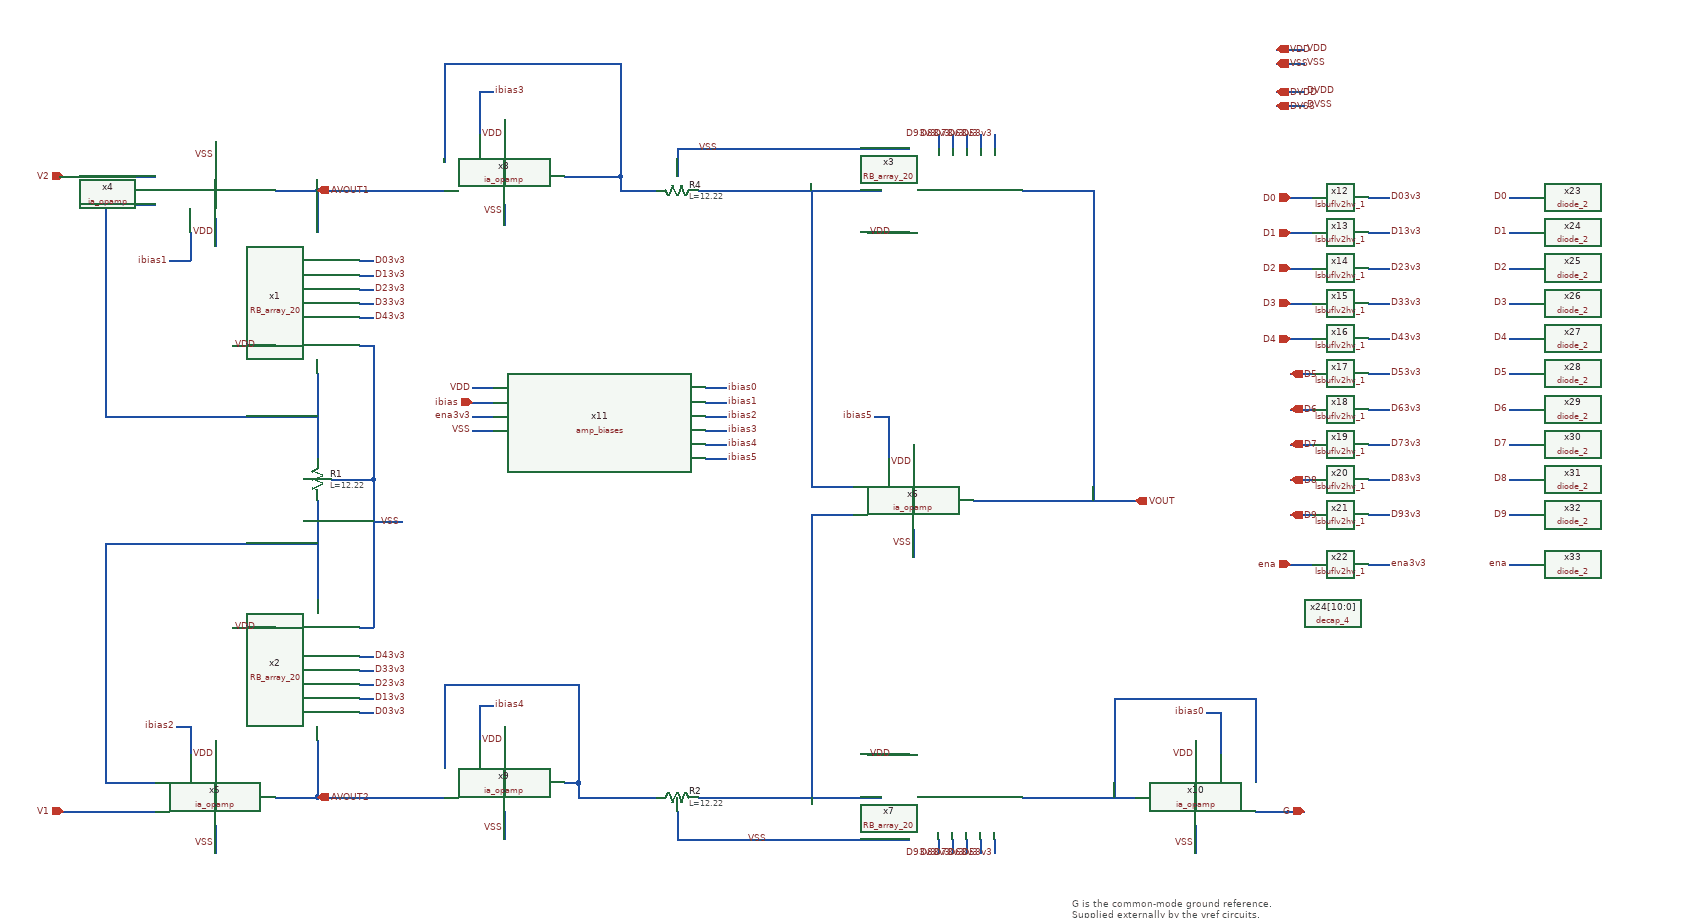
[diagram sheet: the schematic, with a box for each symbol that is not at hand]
v {xschem version=3.4.5 file_version=1.2
}
G {}
K {}
V {}
S {}
E {}
T {G is the common-mode ground reference.
Supplied externally by the vref circuits.} -70 60 0 0 0.4 0.4 {}
N -210 -500 20 -500 {
lab=VOUT}
N -580 -940 -360 -940 {
lab=#net1}
N -140 -940 -40 -940 {
lab=VOUT}
N -40 -940 -40 -500 {
lab=VOUT}
N -580 -80 -360 -80 {
lab=#net2}
N -440 -520 -380 -520 {
lab=#net1}
N -440 -940 -440 -520 {
lab=#net1}
N -440 -480 -380 -480 {
lab=#net2}
N -440 -480 -440 -80 {
lab=#net2}
N -1140 -940 -1140 -880 {
lab=AVOUT1}
N -1140 -660 -1140 -560 {
lab=#net3}
N -1140 -500 -1140 -360 {
lab=#net4}
N -1140 -140 -1140 -80 {
lab=AVOUT2}
N -1440 -920 -1370 -920 {
lab=#net3}
N -1440 -620 -1140 -620 {
lab=#net3}
N -1440 -100 -1370 -100 {
lab=#net4}
N -1440 -440 -1440 -100 {
lab=#net4}
N -1440 -440 -1140 -440 {
lab=#net4}
N -140 -80 20 -80 {
lab=G}
N -295 -580 -295 -540 {
lab=VDD}
N -295 -460 -295 -420 {
lab=VSS}
N -1505 -960 -1370 -960 {
lab=V2}
N -1500 -60 -1370 -60 {
lab=V1}
N -1285 -160 -1285 -120 {
lab=VDD}
N -1285 -40 -1285 0 {
lab=VSS}
N -1285 -900 -1285 -860 {
lab=VDD}
N -1285 -1010 -1285 -980 {
lab=VSS}
N -1060 -690 -1060 -530 {
lab=VSS}
N -1060 -530 -1060 -330 {
lab=VSS}
N -1060 -470 -1020 -470 {
lab=VSS}
N -1440 -890 -1440 -620 {
lab=#net3}
N -1440 -920 -1440 -890 {
lab=#net3}
N -1140 -160 -1140 -140 {
lab=AVOUT2}
N -1080 -320 -1060 -320 {
lab=VSS}
N -1060 -330 -1060 -320 {
lab=VSS}
N -1080 -720 -1060 -720 {
lab=VSS}
N -1060 -720 -1060 -690 {
lab=VSS}
N -1120 -530 -1060 -530 {
lab=VSS}
N -600 -940 -580 -940 {
lab=#net1}
N -630 -1000 -300 -1000 {
lab=VSS}
N -630 -1000 -630 -960 {
lab=VSS}
N -360 -940 -340 -940 {
lab=#net1}
N -360 -80 -340 -80 {
lab=#net2}
N -600 -80 -580 -80 {
lab=#net2}
N -630 -20 -300 -20 {
lab=VSS}
N -1080 -760 -1060 -760 {
lab=D43v3}
N -1080 -780 -1060 -780 {
lab=D33v3}
N -1080 -800 -1060 -800 {
lab=D23v3}
N -1080 -820 -1060 -820 {
lab=D13v3}
N -1080 -840 -1060 -840 {
lab=D03v3}
N -1080 -280 -1060 -280 {
lab=D43v3}
N -1080 -260 -1060 -260 {
lab=D33v3}
N -1080 -240 -1060 -240 {
lab=D23v3}
N -1080 -220 -1060 -220 {
lab=D13v3}
N -1080 -200 -1060 -200 {
lab=D03v3}
N -180 -20 -180 0 {
lab=D53v3}
N -200 -20 -200 0 {
lab=D63v3}
N -220 -20 -220 0 {
lab=D73v3}
N -240 -20 -240 0 {
lab=D83v3}
N -260 -20 -260 0 {
lab=D93v3}
N -180 -1020 -180 -1000 {
lab=D53v3}
N -200 -1020 -200 -1000 {
lab=D63v3}
N -220 -1020 -220 -1000 {
lab=D73v3}
N -240 -1020 -240 -1000 {
lab=D83v3}
N -260 -1020 -260 -1000 {
lab=D93v3}
N -1140 -680 -1140 -660 {
lab=#net3}
N -1260 -720 -1200 -720 {
lab=VDD}
N -1260 -320 -1200 -320 {
lab=VDD}
N -360 -880 -300 -880 {
lab=VDD}
N -360 -140 -300 -140 {
lab=VDD}
N -1200 -940 -1140 -940 {
lab=AVOUT1}
N -1200 -80 -1140 -80 {
lab=AVOUT2}
N -1140 -940 -960 -940 {
lab=AVOUT1}
N -1140 -80 -960 -80 {
lab=AVOUT2}
N -790 -960 -710 -960 {
lab=#net5}
N -710 -940 -660 -940 {
lab=#net5}
N -710 -960 -710 -940 {
lab=#net5}
N -790 -100 -770 -100 {
lab=#net6}
N -770 -80 -660 -80 {
lab=#net6}
N -770 -100 -770 -80 {
lab=#net6}
N -875 -1040 -875 -1000 {
lab=VDD}
N -875 -920 -875 -890 {
lab=VSS}
N -875 -180 -875 -140 {
lab=VDD}
N -875 -60 -875 -20 {
lab=VSS}
N -960 -240 -770 -240 {
lab=#net6}
N 105 -160 105 -120 {
lab=VDD}
N 105 -40 105 0 {
lab=VSS}
N 190 -220 190 -100 {
lab=G}
N -10 -220 190 -220 {
lab=G}
N -10 -220 -10 -80 {
lab=G}
N 190 -60 260 -60 {
lab=G}
N -920 -660 -890 -660 {
lab=VDD}
N -920 -600 -890 -600 {
lab=VSS}
N -920 -620 -890 -620 {
lab=ena3v3}
N -920 -640 -890 -640 {
lab=ibias}
N -590 -660 -560 -660 {
lab=ibias0}
N -590 -640 -560 -640 {
lab=ibias1}
N -590 -620 -560 -620 {
lab=ibias2}
N -590 -600 -560 -600 {
lab=ibias3}
N -590 -580 -560 -580 {
lab=ibias4}
N -590 -560 -560 -560 {
lab=ibias5}
N -1320 -880 -1320 -840 {
lab=ibias1}
N -1350 -840 -1320 -840 {
lab=ibias1}
N -330 -620 -330 -560 {
lab=ibias5}
N -350 -620 -330 -620 {
lab=ibias5}
N 140 -200 140 -140 {
lab=ibias0}
N 120 -200 140 -200 {
lab=ibias0}
N -1320 -180 -1320 -140 {
lab=ibias2}
N -1340 -180 -1320 -180 {
lab=ibias2}
N -960 -240 -960 -120 {
lab=#net6}
N -770 -240 -770 -100 {
lab=#net6}
N -910 -210 -890 -210 {
lab=ibias4}
N -910 -210 -910 -160 {
lab=ibias4}
N -960 -1120 -710 -1120 {
lab=#net5}
N -710 -1120 -710 -960 {
lab=#net5}
N -960 -1120 -960 -980 {
lab=#net5}
N -910 -1080 -890 -1080 {
lab=ibias3}
N -910 -1080 -910 -1020 {
lab=ibias3}
N -630 -60 -630 -20 {
lab=VSS}
N 240 -930 270 -930 {
lab=D0}
N 350 -930 380 -930 {
lab=D03v3}
N 240 -880 270 -880 {
lab=D1}
N 350 -880 380 -880 {
lab=D13v3}
N 240 -830 270 -830 {
lab=D2}
N 350 -830 380 -830 {
lab=D23v3}
N 240 -780 270 -780 {
lab=D3}
N 350 -780 380 -780 {
lab=D33v3}
N 240 -730 270 -730 {
lab=D4}
N 350 -730 380 -730 {
lab=D43v3}
N 240 -680 270 -680 {
lab=D5}
N 350 -680 380 -680 {
lab=D53v3}
N 240 -630 270 -630 {
lab=D6}
N 350 -630 380 -630 {
lab=D63v3}
N 240 -580 270 -580 {
lab=D7}
N 350 -580 380 -580 {
lab=D73v3}
N 240 -530 270 -530 {
lab=D8}
N 350 -530 380 -530 {
lab=D83v3}
N 240 -480 270 -480 {
lab=D9}
N 350 -480 380 -480 {
lab=D93v3}
N 240 -410 270 -410 {
lab=ena}
N 350 -410 380 -410 {
lab=ena3v3}
N 220 -1080 260 -1080 {
lab=DVDD}
N 220 -1060 260 -1060 {
lab=DVSS}
N 220 -1140 260 -1140 {
lab=VDD}
N 220 -1120 260 -1120 {
lab=VSS}
N 550 -930 580 -930 {
lab=D0}
N 550 -880 580 -880 {
lab=D1}
N 550 -830 580 -830 {
lab=D2}
N 550 -780 580 -780 {
lab=D3}
N 550 -730 580 -730 {
lab=D4}
N 550 -680 580 -680 {
lab=D5}
N 550 -630 580 -630 {
lab=D6}
N 550 -580 580 -580 {
lab=D7}
N 550 -530 580 -530 {
lab=D8}
N 550 -480 580 -480 {
lab=D9}
N 550 -410 580 -410 {
lab=ena}
C {devices/opin.sym} 20 -500 0 0 {name=p5 lab=VOUT}
C {devices/lab_wire.sym} -1285 -140 1 0 {name=p2 sig_type=std_logic lab=VDD}
C {devices/lab_wire.sym} -1285 -15 3 0 {name=p4 sig_type=std_logic lab=VSS}
C {devices/lab_wire.sym} -295 -555 1 0 {name=p7 sig_type=std_logic lab=VDD}
C {devices/lab_wire.sym} -1285 -880 3 0 {name=p8 sig_type=std_logic lab=VDD}
C {devices/lab_wire.sym} -295 -440 3 0 {name=p9 sig_type=std_logic lab=VSS}
C {devices/lab_wire.sym} -1285 -990 1 0 {name=p10 sig_type=std_logic lab=VSS}
C {devices/ipin.sym} -1500 -60 0 0 {name=p17 lab=V1
}
C {devices/ipin.sym} -1500 -960 0 0 {name=p18 lab=V2
}
C {ia_opamp.sym} -1220 -940 2 1 {name=x4}
C {ia_opamp.sym} -1220 -80 0 0 {name=x5}
C {ia_opamp.sym} -230 -500 0 0 {name=x6}
C {RB_array_20.sym} -1150 -780 1 0 {name=x1}
C {RB_array_20.sym} -1150 -260 1 1 {name=x2}
C {RB_array_20.sym} -240 -930 0 1 {name=x3}
C {RB_array_20.sym} -240 -90 2 0 {name=x7}
C {devices/opin.sym} -1140 -940 3 0 {name=p38 lab=AVOUT1}
C {devices/opin.sym} -1140 -80 1 0 {name=p39 lab=AVOUT2}
C {devices/lab_wire.sym} -1225 -720 0 0 {name=p40 sig_type=std_logic lab=VDD}
C {devices/lab_wire.sym} -1225 -320 0 0 {name=p41 sig_type=std_logic lab=VDD}
C {devices/lab_wire.sym} -325 -880 0 0 {name=p42 sig_type=std_logic lab=VDD}
C {devices/lab_wire.sym} -325 -140 0 0 {name=p43 sig_type=std_logic lab=VDD}
C {sky130_fd_pr/res_high_po_0p69.sym} -630 -940 1 0 {name=R4
L=12.22
model=res_high_po_0p69
spiceprefix=X
mult=64}
C {sky130_fd_pr/res_high_po_0p69.sym} -1140 -530 2 0 {name=R1
L=12.22
model=res_high_po_0p69
spiceprefix=X
mult=64}
C {sky130_fd_pr/res_high_po_0p69.sym} -630 -80 3 0 {name=R2
L=12.22
model=res_high_po_0p69
spiceprefix=X
mult=64}
C {devices/lab_wire.sym} -875 -1020 1 0 {name=p44 sig_type=std_logic lab=VDD}
C {devices/lab_wire.sym} -875 -910 3 0 {name=p45 sig_type=std_logic lab=VSS}
C {devices/lab_wire.sym} -875 -160 1 0 {name=p46 sig_type=std_logic lab=VDD}
C {devices/lab_wire.sym} -875 -35 3 0 {name=p47 sig_type=std_logic lab=VSS}
C {ia_opamp.sym} -810 -960 0 0 {name=x8}
C {ia_opamp.sym} -810 -100 0 0 {name=x9}
C {devices/lab_wire.sym} 105 -140 3 1 {name=p48 sig_type=std_logic lab=VDD}
C {devices/lab_wire.sym} 105 -15 1 1 {name=p49 sig_type=std_logic lab=VSS}
C {ia_opamp.sym} 40 -80 0 1 {name=x10}
C {devices/iopin.sym} 260 -60 0 0 {name=p1 lab=G}
C {amp_biases.sym} -740 -610 0 0 {name=x11}
C {devices/lab_pin.sym} -920 -660 0 0 {name=p51 sig_type=std_logic lab=VDD}
C {devices/lab_pin.sym} -920 -600 0 0 {name=p54 sig_type=std_logic lab=VSS}
C {devices/lab_pin.sym} -560 -660 0 1 {name=p55 sig_type=std_logic lab=ibias0
}
C {devices/lab_pin.sym} -560 -640 0 1 {name=p56 sig_type=std_logic lab=ibias1
}
C {devices/lab_pin.sym} -560 -620 0 1 {name=p57 sig_type=std_logic lab=ibias2
}
C {devices/lab_pin.sym} -560 -600 0 1 {name=p58 sig_type=std_logic lab=ibias3}
C {devices/lab_pin.sym} -560 -580 0 1 {name=p59 sig_type=std_logic lab=ibias4
}
C {devices/lab_pin.sym} -560 -560 0 1 {name=p60 sig_type=std_logic lab=ibias5
}
C {devices/lab_pin.sym} 120 -200 0 0 {name=p61 sig_type=std_logic lab=ibias0}
C {devices/lab_pin.sym} -1350 -840 0 0 {name=p62 sig_type=std_logic lab=ibias1}
C {devices/lab_pin.sym} -1340 -180 0 0 {name=p63 sig_type=std_logic lab=ibias2}
C {devices/lab_pin.sym} -890 -1080 0 1 {name=p64 sig_type=std_logic lab=ibias3}
C {devices/lab_pin.sym} -890 -210 0 1 {name=p65 sig_type=std_logic lab=ibias4}
C {devices/lab_pin.sym} -350 -620 0 0 {name=p66 sig_type=std_logic lab=ibias5}
C {devices/lab_wire.sym} -1020 -470 0 0 {name=p11 sig_type=std_logic lab=VSS}
C {devices/lab_wire.sym} -570 -1000 0 0 {name=p12 sig_type=std_logic lab=VSS}
C {devices/lab_wire.sym} -500 -20 0 0 {name=p13 sig_type=std_logic lab=VSS}
C {lsbuflv2hv_1.sym} 310 -930 0 0 {name=x12 LVPWR=DVDD VGND=DVSS VNB=DVSS VPB=VDD VPWR=VDD prefix=sky130_fd_sc_hvl__ }
C {devices/iopin.sym} 220 -1080 0 1 {name=p67 lab=DVDD}
C {devices/iopin.sym} 220 -1060 0 1 {name=p68 lab=DVSS}
C {devices/lab_pin.sym} 380 -930 0 1 {name=p70 sig_type=std_logic lab=D03v3}
C {lsbuflv2hv_1.sym} 310 -880 0 0 {name=x13 LVPWR=DVDD VGND=DVSS VNB=DVSS VPB=VDD VPWR=VDD prefix=sky130_fd_sc_hvl__ }
C {devices/lab_pin.sym} 380 -880 0 1 {name=p72 sig_type=std_logic lab=D13v3}
C {lsbuflv2hv_1.sym} 310 -830 0 0 {name=x14 LVPWR=DVDD VGND=DVSS VNB=DVSS VPB=VDD VPWR=VDD prefix=sky130_fd_sc_hvl__ }
C {devices/lab_pin.sym} 380 -830 0 1 {name=p74 sig_type=std_logic lab=D23v3}
C {lsbuflv2hv_1.sym} 310 -780 0 0 {name=x15 LVPWR=DVDD VGND=DVSS VNB=DVSS VPB=VDD VPWR=VDD prefix=sky130_fd_sc_hvl__ }
C {devices/lab_pin.sym} 380 -780 0 1 {name=p76 sig_type=std_logic lab=D33v3}
C {lsbuflv2hv_1.sym} 310 -730 0 0 {name=x16 LVPWR=DVDD VGND=DVSS VNB=DVSS VPB=VDD VPWR=VDD prefix=sky130_fd_sc_hvl__ }
C {devices/lab_pin.sym} 380 -730 0 1 {name=p78 sig_type=std_logic lab=D43v3}
C {lsbuflv2hv_1.sym} 310 -680 0 0 {name=x17 LVPWR=DVDD VGND=DVSS VNB=DVSS VPB=VDD VPWR=VDD prefix=sky130_fd_sc_hvl__ }
C {devices/lab_pin.sym} 380 -680 0 1 {name=p80 sig_type=std_logic lab=D53v3}
C {lsbuflv2hv_1.sym} 310 -630 0 0 {name=x18 LVPWR=DVDD VGND=DVSS VNB=DVSS VPB=VDD VPWR=VDD prefix=sky130_fd_sc_hvl__ }
C {devices/lab_pin.sym} 380 -630 0 1 {name=p82 sig_type=std_logic lab=D63v3}
C {lsbuflv2hv_1.sym} 310 -580 0 0 {name=x19 LVPWR=DVDD VGND=DVSS VNB=DVSS VPB=VDD VPWR=VDD prefix=sky130_fd_sc_hvl__ }
C {devices/lab_pin.sym} 380 -580 0 1 {name=p84 sig_type=std_logic lab=D73v3}
C {lsbuflv2hv_1.sym} 310 -530 0 0 {name=x20 LVPWR=DVDD VGND=DVSS VNB=DVSS VPB=VDD VPWR=VDD prefix=sky130_fd_sc_hvl__ }
C {devices/lab_pin.sym} 380 -530 0 1 {name=p86 sig_type=std_logic lab=D83v3}
C {lsbuflv2hv_1.sym} 310 -480 0 0 {name=x21 LVPWR=DVDD VGND=DVSS VNB=DVSS VPB=VDD VPWR=VDD prefix=sky130_fd_sc_hvl__ }
C {devices/lab_pin.sym} 380 -480 0 1 {name=p88 sig_type=std_logic lab=D93v3}
C {devices/ipin.sym} 240 -730 0 0 {name=p89 lab=D4
}
C {devices/ipin.sym} 240 -780 0 0 {name=p90 lab=D3
}
C {devices/ipin.sym} 240 -830 0 0 {name=p91 lab=D2
}
C {devices/ipin.sym} 240 -880 0 0 {name=p92 lab=D1
}
C {devices/ipin.sym} 240 -930 0 0 {name=p93 lab=D0
}
C {devices/ipin.sym} 240 -480 2 1 {name=p94 lab=D9
}
C {devices/ipin.sym} 240 -530 2 1 {name=p95 lab=D8
}
C {devices/ipin.sym} 240 -580 2 1 {name=p96 lab=D7
}
C {devices/ipin.sym} 240 -630 2 1 {name=p97 lab=D6
}
C {devices/ipin.sym} 240 -680 2 1 {name=p98 lab=D5
}
C {devices/lab_pin.sym} -1060 -840 0 1 {name=p14 sig_type=std_logic lab=D03v3}
C {devices/lab_pin.sym} -1060 -820 0 1 {name=p19 sig_type=std_logic lab=D13v3}
C {devices/lab_pin.sym} -1060 -800 0 1 {name=p20 sig_type=std_logic lab=D23v3}
C {devices/lab_pin.sym} -1060 -780 0 1 {name=p21 sig_type=std_logic lab=D33v3}
C {devices/lab_pin.sym} -1060 -760 0 1 {name=p22 sig_type=std_logic lab=D43v3}
C {devices/lab_pin.sym} -1060 -200 0 1 {name=p23 sig_type=std_logic lab=D03v3}
C {devices/lab_pin.sym} -1060 -220 0 1 {name=p24 sig_type=std_logic lab=D13v3}
C {devices/lab_pin.sym} -1060 -240 0 1 {name=p25 sig_type=std_logic lab=D23v3}
C {devices/lab_pin.sym} -1060 -260 0 1 {name=p26 sig_type=std_logic lab=D33v3}
C {devices/lab_pin.sym} -1060 -280 0 1 {name=p27 sig_type=std_logic lab=D43v3}
C {devices/lab_pin.sym} -180 0 3 0 {name=p28 sig_type=std_logic lab=D53v3}
C {devices/lab_pin.sym} -200 0 3 0 {name=p29 sig_type=std_logic lab=D63v3}
C {devices/lab_pin.sym} -220 0 3 0 {name=p30 sig_type=std_logic lab=D73v3}
C {devices/lab_pin.sym} -240 0 3 0 {name=p31 sig_type=std_logic lab=D83v3}
C {devices/lab_pin.sym} -260 0 3 0 {name=p32 sig_type=std_logic lab=D93v3}
C {devices/lab_pin.sym} -180 -1020 1 0 {name=p33 sig_type=std_logic lab=D53v3}
C {devices/lab_pin.sym} -200 -1020 1 0 {name=p34 sig_type=std_logic lab=D63v3}
C {devices/lab_pin.sym} -220 -1020 1 0 {name=p35 sig_type=std_logic lab=D73v3}
C {devices/lab_pin.sym} -240 -1020 1 0 {name=p36 sig_type=std_logic lab=D83v3}
C {devices/lab_pin.sym} -260 -1020 1 0 {name=p37 sig_type=std_logic lab=D93v3}
C {devices/ipin.sym} -920 -640 0 0 {name=p52 lab=ibias}
C {lsbuflv2hv_1.sym} 310 -410 0 0 {name=x22 LVPWR=DVDD VGND=DVSS VNB=DVSS VPB=VDD VPWR=VDD prefix=sky130_fd_sc_hvl__ }
C {devices/lab_pin.sym} 380 -410 0 1 {name=p100 sig_type=std_logic lab=ena3v3}
C {devices/ipin.sym} 240 -410 0 0 {name=p99 lab=ena}
C {devices/lab_pin.sym} -920 -620 0 0 {name=p53 sig_type=std_logic lab=ena3v3}
C {devices/lab_pin.sym} 260 -1120 0 1 {name=p69 sig_type=std_logic lab=VSS}
C {devices/lab_pin.sym} 260 -1140 0 1 {name=p71 sig_type=std_logic lab=VDD}
C {devices/iopin.sym} 220 -1140 0 1 {name=p3 lab=VDD}
C {devices/iopin.sym} 220 -1120 0 1 {name=p6 lab=VSS}
C {devices/lab_pin.sym} 260 -1060 0 1 {name=p73 sig_type=std_logic lab=DVSS}
C {devices/lab_pin.sym} 260 -1080 0 1 {name=p75 sig_type=std_logic lab=DVDD}
C {sky130_stdcells/diode_2.sym} 670 -930 0 0 {name=x23 VGND=DVSS VNB=DVSS VPB=VDD VPWR=VDD prefix=sky130_fd_sc_hvl__ }
C {sky130_stdcells/decap_4.sym} 300 -340 0 0 {name=x24[10:0] VGND=DVSS VNB=DVSS VPB=VDD VPWR=VDD prefix=sky130_fd_sc_hvl__ }
C {devices/lab_pin.sym} 550 -930 0 0 {name=p15 sig_type=std_logic lab=D0}
C {sky130_stdcells/diode_2.sym} 670 -880 0 0 {name=x24 VGND=DVSS VNB=DVSS VPB=VDD VPWR=VDD prefix=sky130_fd_sc_hvl__ }
C {devices/lab_pin.sym} 550 -880 0 0 {name=p16 sig_type=std_logic lab=D1}
C {sky130_stdcells/diode_2.sym} 670 -830 0 0 {name=x25 VGND=DVSS VNB=DVSS VPB=VDD VPWR=VDD prefix=sky130_fd_sc_hvl__ }
C {devices/lab_pin.sym} 550 -830 0 0 {name=p77 sig_type=std_logic lab=D2}
C {sky130_stdcells/diode_2.sym} 670 -780 0 0 {name=x26 VGND=DVSS VNB=DVSS VPB=VDD VPWR=VDD prefix=sky130_fd_sc_hvl__ }
C {devices/lab_pin.sym} 550 -780 0 0 {name=p79 sig_type=std_logic lab=D3}
C {sky130_stdcells/diode_2.sym} 670 -730 0 0 {name=x27 VGND=DVSS VNB=DVSS VPB=VDD VPWR=VDD prefix=sky130_fd_sc_hvl__ }
C {devices/lab_pin.sym} 550 -730 0 0 {name=p81 sig_type=std_logic lab=D4}
C {sky130_stdcells/diode_2.sym} 670 -680 0 0 {name=x28 VGND=DVSS VNB=DVSS VPB=VDD VPWR=VDD prefix=sky130_fd_sc_hvl__ }
C {devices/lab_pin.sym} 550 -680 0 0 {name=p83 sig_type=std_logic lab=D5}
C {sky130_stdcells/diode_2.sym} 670 -630 0 0 {name=x29 VGND=DVSS VNB=DVSS VPB=VDD VPWR=VDD prefix=sky130_fd_sc_hvl__ }
C {devices/lab_pin.sym} 550 -630 0 0 {name=p85 sig_type=std_logic lab=D6}
C {sky130_stdcells/diode_2.sym} 670 -580 0 0 {name=x30 VGND=DVSS VNB=DVSS VPB=VDD VPWR=VDD prefix=sky130_fd_sc_hvl__ }
C {devices/lab_pin.sym} 550 -580 0 0 {name=p87 sig_type=std_logic lab=D7}
C {sky130_stdcells/diode_2.sym} 670 -530 0 0 {name=x31 VGND=DVSS VNB=DVSS VPB=VDD VPWR=VDD prefix=sky130_fd_sc_hvl__ }
C {devices/lab_pin.sym} 550 -530 0 0 {name=p101 sig_type=std_logic lab=D8}
C {sky130_stdcells/diode_2.sym} 670 -480 0 0 {name=x32 VGND=DVSS VNB=DVSS VPB=VDD VPWR=VDD prefix=sky130_fd_sc_hvl__ }
C {devices/lab_pin.sym} 550 -480 0 0 {name=p102 sig_type=std_logic lab=D9}
C {sky130_stdcells/diode_2.sym} 670 -410 0 0 {name=x33 VGND=DVSS VNB=DVSS VPB=VDD VPWR=VDD prefix=sky130_fd_sc_hvl__ }
C {devices/lab_pin.sym} 550 -410 0 0 {name=p103 sig_type=std_logic lab=ena}
